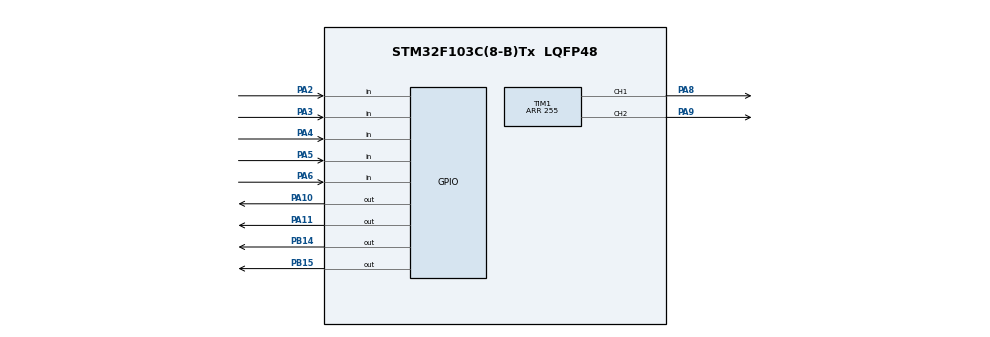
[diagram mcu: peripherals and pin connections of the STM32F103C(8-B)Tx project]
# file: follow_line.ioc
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Mcu.Family=STM32F1
Mcu.Name=STM32F103C(8-B)Tx
Mcu.Package=LQFP48
NVIC.PriorityGroup=NVIC_PRIORITYGROUP_4
PA10.Signal=GPIO_Output
PA11.Signal=GPIO_Output
PA13.Mode=Serial_Wire
PA13.Signal=SYS_JTMS-SWDIO
PA14.Mode=Serial_Wire
PA14.Signal=SYS_JTCK-SWCLK
PA2.Signal=GPIO_Input
PA3.Signal=GPIO_Input
PA4.Signal=GPIO_Input
PA5.Signal=GPIO_Input
PA6.Signal=GPIO_Input
PA8.Signal=S_TIM1_CH1
PA9.Signal=S_TIM1_CH2
PB14.Signal=GPIO_Output
PB15.Signal=GPIO_Output
PD0-OSC_IN.Mode=HSE-External-Oscillator
PD0-OSC_IN.Signal=RCC_OSC_IN
PD1-OSC_OUT.Mode=HSE-External-Oscillator
PD1-OSC_OUT.Signal=RCC_OSC_OUT
ProjectManager.HeapSize=0x200
ProjectManager.StackSize=0x400
ProjectManager.TargetToolchain=STM32CubeIDE
RCC.APB1Freq_Value=8000000
RCC.APB2Freq_Value=8000000
SH.S_TIM1_CH1.0=TIM1_CH1,PWM Generation1 CH1
SH.S_TIM1_CH2.0=TIM1_CH2,PWM Generation2 CH2
TIM1.AutoReloadPreload=TIM_AUTORELOAD_PRELOAD_ENABLE
TIM1.Channel-PWM\ Generation1\ CH1=TIM_CHANNEL_1
TIM1.Channel-PWM\ Generation2\ CH2=TIM_CHANNEL_2
TIM1.Period=255
VP_TIM1_VS_ClockSourceINT.Mode=Internal
board=custom

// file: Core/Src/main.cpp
/* USER CODE BEGIN Header */
/**
  ******************************************************************************
  * @file           : main.c
  * @brief          : Main program body
  ******************************************************************************
  * @attention
  *
  * Copyright (c) 2024 STMicroelectronics.
  * All rights reserved.
  *
  * This software is licensed under terms that can be found in the LICENSE file
  * in the root directory of this software component.
  * If no LICENSE file comes with this software, it is provided AS-IS.
  *
  ******************************************************************************
  */
/* USER CODE END Header */
#include "main.h"
#include "Motor.h"

/* USER CODE BEGIN Includes */
//int IR_lm;
//int IR_l;
//int IR_c;
//int IR_r;
//int IR_rm;

/* USER CODE END Includes */

TIM_HandleTypeDef htim1;

void SystemClock_Config(void);
static void MX_GPIO_Init(void);
static void MX_TIM1_Init(void);

int main(void)
{

  /* MCU Configuration--------------------------------------------------------*/

  /* Reset of all peripherals, Initializes the Flash interface and the Systick. */
  HAL_Init();

  /* Configure the system clock */
  SystemClock_Config();

  /* Initialize all configured peripherals */
  MX_GPIO_Init();
  MX_TIM1_Init();
  /* USER CODE BEGIN 2 */
  MOTOR MotorA(GPIOB, GPIO_PIN_14, GPIOB, GPIO_PIN_15);
  MotorA.motor_init(&htim1, TIM_CHANNEL_1);
  MOTOR MotorB(GPIOA, GPIO_PIN_10, GPIOA, GPIO_PIN_11);
  MotorB.motor_init(&htim1, TIM_CHANNEL_2);

  /* USER CODE END 2 */

  /* Infinite loop */
  while (1)
  {
	  //forward
	  	  if(HAL_GPIO_ReadPin(GPIOA, GPIO_PIN_2)== 0 && HAL_GPIO_ReadPin(GPIOA,GPIO_PIN_3) == 0 && HAL_GPIO_ReadPin(GPIOA, GPIO_PIN_4)== 1 &&HAL_GPIO_ReadPin(GPIOA, GPIO_PIN_5)== 0 &&HAL_GPIO_ReadPin(GPIOA, GPIO_PIN_6)== 0) {
	  		  MotorA.anti_clockwise(25);
	  		  MotorB.clockwise(30);
	  	  }

	  //left turn
	  	  else if(HAL_GPIO_ReadPin(GPIOA, GPIO_PIN_2) == 0 && HAL_GPIO_ReadPin(GPIOA,GPIO_PIN_3)== 1 && HAL_GPIO_ReadPin(GPIOA, GPIO_PIN_4) == 1 && HAL_GPIO_ReadPin(GPIOA, GPIO_PIN_5)== 0 &&HAL_GPIO_ReadPin(GPIOA, GPIO_PIN_6)== 0) {
	  	  		  MotorA.anti_clockwise(30);
	  	  		  MotorB.clockwise(25);
	  	  }
	  	  else if(HAL_GPIO_ReadPin(GPIOA, GPIO_PIN_2)== 1 && HAL_GPIO_ReadPin(GPIOA,GPIO_PIN_3)== 0  && HAL_GPIO_ReadPin(GPIOA, GPIO_PIN_4)== 0 && HAL_GPIO_ReadPin(GPIOA, GPIO_PIN_5)== 0 &&HAL_GPIO_ReadPin(GPIOA, GPIO_PIN_6)== 0){
	  		      MotorA.anti_clockwise(30);
	  		      MotorB.clockwise(25);

	  	  }
	  	  else if(HAL_GPIO_ReadPin(GPIOA, GPIO_PIN_2) == 0 && HAL_GPIO_ReadPin(GPIOA,GPIO_PIN_3)== 1 && HAL_GPIO_ReadPin(GPIOA, GPIO_PIN_4)== 0 &&HAL_GPIO_ReadPin(GPIOA, GPIO_PIN_5)== 0 &&HAL_GPIO_ReadPin(GPIOA, GPIO_PIN_6)== 0 ){
	  		      MotorA.anti_clockwise(30);
	  		      MotorB.anti_clockwise(20);

	  	  }

	  	  //sharp left turn
          else if(HAL_GPIO_ReadPin(GPIOA, GPIO_PIN_2) == 1 && HAL_GPIO_ReadPin(GPIOA,GPIO_PIN_3)== 1 && HAL_GPIO_ReadPin(GPIOA, GPIO_PIN_4)==  1 &&HAL_GPIO_ReadPin(GPIOA, GPIO_PIN_5)== 0 &&HAL_GPIO_ReadPin(GPIOA, GPIO_PIN_6)== 0 ){
	  	 		  MotorA.anti_clockwise(30);
	  	 		  MotorB.clockwise(20);

	  	 	  }
	  	  else if(HAL_GPIO_ReadPin(GPIOA, GPIO_PIN_2) == 1 && HAL_GPIO_ReadPin(GPIOA,GPIO_PIN_3) == 1 && HAL_GPIO_ReadPin(GPIOA, GPIO_PIN_4)== 0 && HAL_GPIO_ReadPin(GPIOA, GPIO_PIN_5)== 0 &&HAL_GPIO_ReadPin(GPIOA, GPIO_PIN_6)== 0 ){
	  		      MotorA.anti_clockwise(30);
	  	          MotorB.clockwise(15);
	  	  	    }
	  	  //right turn
	  	  else if(HAL_GPIO_ReadPin(GPIOA, GPIO_PIN_2) == 0 && HAL_GPIO_ReadPin(GPIOA,GPIO_PIN_3) == 0 && HAL_GPIO_ReadPin(GPIOA, GPIO_PIN_4)== 1 && HAL_GPIO_ReadPin(GPIOA, GPIO_PIN_5)== 1 && HAL_GPIO_ReadPin(GPIOA, GPIO_PIN_6)== 0) {
	  		     MotorA.anti_clockwise(30);
	  		     MotorB.clockwise(15);
	  	  	 	 }

	  	  else if(HAL_GPIO_ReadPin(GPIOA, GPIO_PIN_2) == 0 && HAL_GPIO_ReadPin(GPIOA,GPIO_PIN_3) == 0 && HAL_GPIO_ReadPin(GPIOA, GPIO_PIN_4)== 0 && HAL_GPIO_ReadPin(GPIOA, GPIO_PIN_5)== 0 && HAL_GPIO_ReadPin(GPIOA, GPIO_PIN_6)== 1) {
	  		  		     MotorA.anti_clockwise(30);
	  		  		     MotorB.clockwise(15);
	  		  	  	 	 }
	  	 else if(HAL_GPIO_ReadPin(GPIOA, GPIO_PIN_2) == 0 && HAL_GPIO_ReadPin(GPIOA,GPIO_PIN_3) == 0 && HAL_GPIO_ReadPin(GPIOA, GPIO_PIN_4)== 0 && HAL_GPIO_ReadPin(GPIOA, GPIO_PIN_5)== 1 && HAL_GPIO_ReadPin(GPIOA, GPIO_PIN_6)== 0) {
	  		  		  		     MotorA.anti_clockwise(30);
	  		  		  		     MotorB.clockwise(15);
	  		  		  	  	 	 }
	  	  //sharp right turnb
	  	 else if(HAL_GPIO_ReadPin(GPIOA, GPIO_PIN_2) == 0 && HAL_GPIO_ReadPin(GPIOA,GPIO_PIN_3) == 0 && HAL_GPIO_ReadPin(GPIOA, GPIO_PIN_4)== 1 && HAL_GPIO_ReadPin(GPIOA, GPIO_PIN_5)== 1 && HAL_GPIO_ReadPin(GPIOA, GPIO_PIN_6)== 1) {
	  		  		     MotorA.anti_clockwise(30);
	  		  		     MotorB.clockwise(15);
	  		  	  	 	 }

	     else if(HAL_GPIO_ReadPin(GPIOA, GPIO_PIN_2) == 0 && HAL_GPIO_ReadPin(GPIOA,GPIO_PIN_3) == 0 && HAL_GPIO_ReadPin(GPIOA, GPIO_PIN_4)== 0 && HAL_GPIO_ReadPin(GPIOA, GPIO_PIN_5)== 1 && HAL_GPIO_ReadPin(GPIOA, GPIO_PIN_6)== 1) {
	  		  		  		     MotorA.anti_clockwise(30);
	  		  		  		     MotorB.clockwise(15);
	  		  		  	  	 	 }

          else{
	  	 	  	  MotorA.brake();
	  	 	  	  MotorB.brake();
	  	 	  	 }

  }
}

void SystemClock_Config(void)
{
  RCC_OscInitTypeDef RCC_OscInitStruct = {0};
  RCC_ClkInitTypeDef RCC_ClkInitStruct = {0};

  /** Initializes the RCC Oscillators according to the specified parameters
  * in the RCC_OscInitTypeDef structure.
  */
  RCC_OscInitStruct.OscillatorType = RCC_OSCILLATORTYPE_HSE;
  RCC_OscInitStruct.HSEState = RCC_HSE_ON;
  RCC_OscInitStruct.HSEPredivValue = RCC_HSE_PREDIV_DIV1;
  RCC_OscInitStruct.HSIState = RCC_HSI_ON;
  RCC_OscInitStruct.PLL.PLLState = RCC_PLL_ON;
  RCC_OscInitStruct.PLL.PLLSource = RCC_PLLSOURCE_HSE;
  RCC_OscInitStruct.PLL.PLLMUL = RCC_PLL_MUL9;
  if (HAL_RCC_OscConfig(&RCC_OscInitStruct) != HAL_OK)
  {
    Error_Handler();
  }

  /** Initializes the CPU, AHB and APB buses clocks
  */
  RCC_ClkInitStruct.ClockType = RCC_CLOCKTYPE_HCLK|RCC_CLOCKTYPE_SYSCLK
                              |RCC_CLOCKTYPE_PCLK1|RCC_CLOCKTYPE_PCLK2;
  RCC_ClkInitStruct.SYSCLKSource = RCC_SYSCLKSOURCE_PLLCLK;
  RCC_ClkInitStruct.AHBCLKDivider = RCC_SYSCLK_DIV1;
  RCC_ClkInitStruct.APB1CLKDivider = RCC_HCLK_DIV2;
  RCC_ClkInitStruct.APB2CLKDivider = RCC_HCLK_DIV1;

  if (HAL_RCC_ClockConfig(&RCC_ClkInitStruct, FLASH_LATENCY_2) != HAL_OK)
  {
    Error_Handler();
  }
}

static void MX_TIM1_Init(void)
{

  TIM_ClockConfigTypeDef sClockSourceConfig = {0};
  TIM_MasterConfigTypeDef sMasterConfig = {0};
  TIM_OC_InitTypeDef sConfigOC = {0};
  TIM_BreakDeadTimeConfigTypeDef sBreakDeadTimeConfig = {0};

  htim1.Instance = TIM1;
  htim1.Init.Prescaler = 0;
  htim1.Init.CounterMode = TIM_COUNTERMODE_UP;
  htim1.Init.Period = 255;
  htim1.Init.ClockDivision = TIM_CLOCKDIVISION_DIV1;
  htim1.Init.RepetitionCounter = 0;
  htim1.Init.AutoReloadPreload = TIM_AUTORELOAD_PRELOAD_ENABLE;
  if (HAL_TIM_Base_Init(&htim1) != HAL_OK)
  {
    Error_Handler();
  }
  sClockSourceConfig.ClockSource = TIM_CLOCKSOURCE_INTERNAL;
  if (HAL_TIM_ConfigClockSource(&htim1, &sClockSourceConfig) != HAL_OK)
  {
    Error_Handler();
  }
  if (HAL_TIM_PWM_Init(&htim1) != HAL_OK)
  {
    Error_Handler();
  }
  sMasterConfig.MasterOutputTrigger = TIM_TRGO_RESET;
  sMasterConfig.MasterSlaveMode = TIM_MASTERSLAVEMODE_DISABLE;
  if (HAL_TIMEx_MasterConfigSynchronization(&htim1, &sMasterConfig) != HAL_OK)
  {
    Error_Handler();
  }
  sConfigOC.OCMode = TIM_OCMODE_PWM1;
  sConfigOC.Pulse = 0;
  sConfigOC.OCPolarity = TIM_OCPOLARITY_HIGH;
  sConfigOC.OCNPolarity = TIM_OCNPOLARITY_HIGH;
  sConfigOC.OCFastMode = TIM_OCFAST_DISABLE;
  sConfigOC.OCIdleState = TIM_OCIDLESTATE_RESET;
  sConfigOC.OCNIdleState = TIM_OCNIDLESTATE_RESET;
  if (HAL_TIM_PWM_ConfigChannel(&htim1, &sConfigOC, TIM_CHANNEL_1) != HAL_OK)
  {
    Error_Handler();
  }
  if (HAL_TIM_PWM_ConfigChannel(&htim1, &sConfigOC, TIM_CHANNEL_2) != HAL_OK)
  {
    Error_Handler();
  }
  sBreakDeadTimeConfig.OffStateRunMode = TIM_OSSR_DISABLE;
  sBreakDeadTimeConfig.OffStateIDLEMode = TIM_OSSI_DISABLE;
  sBreakDeadTimeConfig.LockLevel = TIM_LOCKLEVEL_OFF;
  sBreakDeadTimeConfig.DeadTime = 0;
  sBreakDeadTimeConfig.BreakState = TIM_BREAK_DISABLE;
  sBreakDeadTimeConfig.BreakPolarity = TIM_BREAKPOLARITY_HIGH;
  sBreakDeadTimeConfig.AutomaticOutput = TIM_AUTOMATICOUTPUT_DISABLE;
  if (HAL_TIMEx_ConfigBreakDeadTime(&htim1, &sBreakDeadTimeConfig) != HAL_OK)
  {
    Error_Handler();
  }
  HAL_TIM_MspPostInit(&htim1);

}

static void MX_GPIO_Init(void)
{
  GPIO_InitTypeDef GPIO_InitStruct = {0};

  /* GPIO Ports Clock Enable */
  __HAL_RCC_GPIOD_CLK_ENABLE();
  __HAL_RCC_GPIOA_CLK_ENABLE();
  __HAL_RCC_GPIOB_CLK_ENABLE();

  /*Configure GPIO pin Output Level */
  HAL_GPIO_WritePin(GPIOB, GPIO_PIN_14|GPIO_PIN_15, GPIO_PIN_RESET);

  /*Configure GPIO pin Output Level */
  HAL_GPIO_WritePin(GPIOA, GPIO_PIN_10|GPIO_PIN_11, GPIO_PIN_RESET);

  /*Configure GPIO pins : PA2 PA3 PA4 PA5
                           PA6 */
  GPIO_InitStruct.Pin = GPIO_PIN_2|GPIO_PIN_3|GPIO_PIN_4|GPIO_PIN_5
                          |GPIO_PIN_6;
  GPIO_InitStruct.Mode = GPIO_MODE_INPUT;
  GPIO_InitStruct.Pull = GPIO_NOPULL;
  HAL_GPIO_Init(GPIOA, &GPIO_InitStruct);

  /*Configure GPIO pins : PB14 PB15 */
  GPIO_InitStruct.Pin = GPIO_PIN_14|GPIO_PIN_15;
  GPIO_InitStruct.Mode = GPIO_MODE_OUTPUT_PP;
  GPIO_InitStruct.Pull = GPIO_NOPULL;
  GPIO_InitStruct.Speed = GPIO_SPEED_FREQ_LOW;
  HAL_GPIO_Init(GPIOB, &GPIO_InitStruct);

  /*Configure GPIO pins : PA10 PA11 */
  GPIO_InitStruct.Pin = GPIO_PIN_10|GPIO_PIN_11;
  GPIO_InitStruct.Mode = GPIO_MODE_OUTPUT_PP;
  GPIO_InitStruct.Pull = GPIO_NOPULL;
  GPIO_InitStruct.Speed = GPIO_SPEED_FREQ_LOW;
  HAL_GPIO_Init(GPIOA, &GPIO_InitStruct);

}

void Error_Handler(void)
{
  __disable_irq();
  while (1)
  {
  }
}
